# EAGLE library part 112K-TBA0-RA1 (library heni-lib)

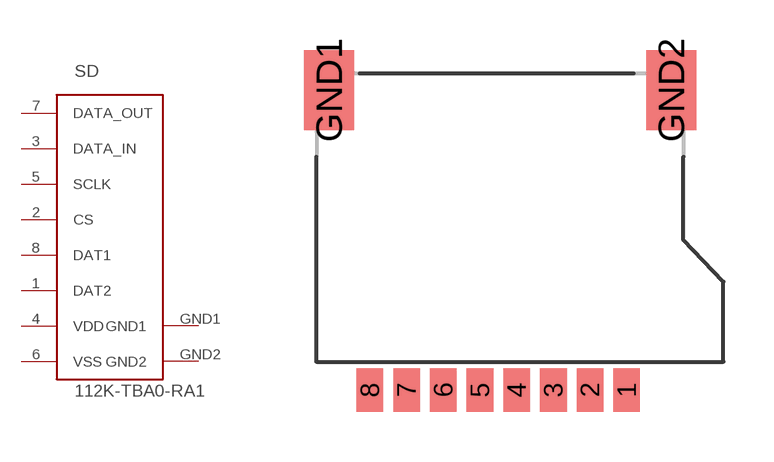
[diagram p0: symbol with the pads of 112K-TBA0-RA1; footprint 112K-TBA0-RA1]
Designator prefix SD

## 112K-TBA0-RA1  [112K-TBA0-RA1]
1  DAT2
2  CS
3  DATA_IN
4  VDD
5  SCLK
6  VSS
7  DATA_OUT
8  DAT1
GND1  GND1
GND2  GND2

## Footprint 112K-TBA0-RA1 (pad centres in mm)
smd 0.8 x 1.3: 1 3.2,0; 2 2.1,0; 3 1,0; 4 -0.1,0; 5 -1.2,0; 6 -2.3,0; 7 -3.4,0; 8 -4.5,0
smd 1.5 x 2.4: GND1 -5.73,9; GND2 4.53,9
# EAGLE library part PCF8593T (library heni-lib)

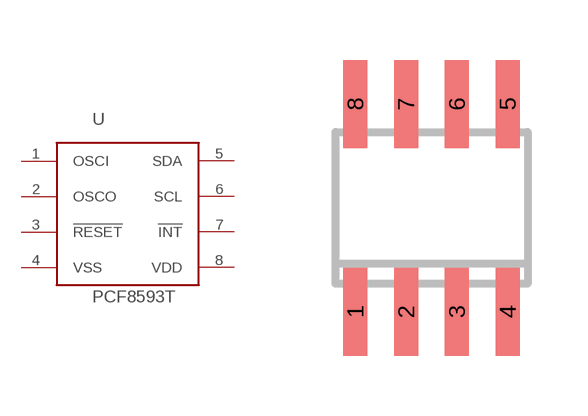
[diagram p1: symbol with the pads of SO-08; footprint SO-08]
Designator prefix U

## PCF8593T  [SO-08]
1  OSCI
2  OSCO
3  !RESET
4  VSS
5  SDA
6  SCL
7  !INT
8  VDD

## Footprint SO-08 (pad centres in mm)
Small Outline Narrow Plastic Gull Wing 150-mil body, package type SN
smd 0.6 x 2.2: 1 -1.905,-2.6; 2 -0.635,-2.6; 3 0.635,-2.6; 4 1.905,-2.6; 5 1.905,2.6; 6 0.635,2.6; 7 -0.635,2.6; 8 -1.905,2.6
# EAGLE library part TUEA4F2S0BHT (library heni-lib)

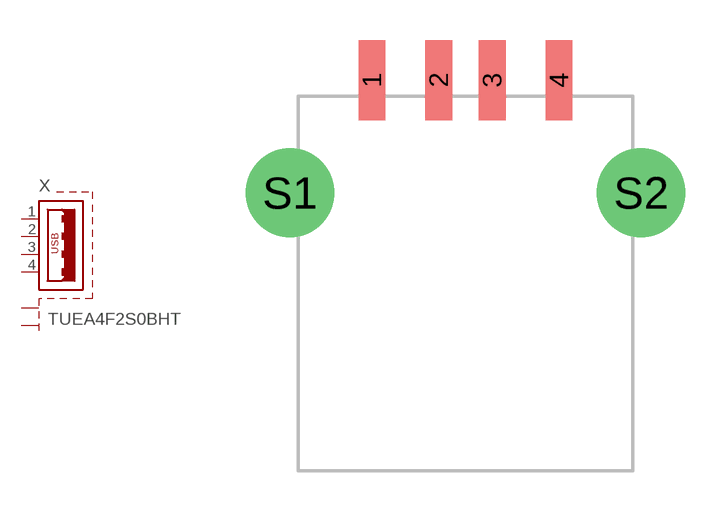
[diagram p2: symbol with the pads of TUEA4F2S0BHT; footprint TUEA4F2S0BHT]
Designator prefix X

## TUEA4F2S0BHT  [TUEA4F2S0BHT]
1  VCC  pas
2  D-  pas
3  D+  pas
4  GND  pas
S1  S1  pas
S2  S2  pas

## Footprint TUEA4F2S0BHT (pad centres in mm)
smd 1 x 3: 1 -3.5,14.61; 2 -1,14.61; 3 1,14.61; 4 3.5,14.61
drill 2.3: S1 -6.57,10.4; S2 6.57,10.4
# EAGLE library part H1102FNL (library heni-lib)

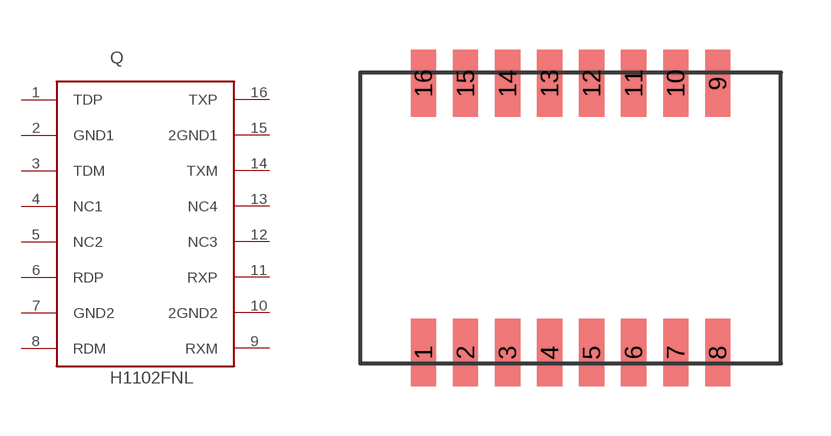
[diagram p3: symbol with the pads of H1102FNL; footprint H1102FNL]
Designator prefix Q

## H1102FNL  [H1102FNL]
1  TDP
2  GND1
3  TDM
4  NC1
5  NC2
6  RDP
7  GND2
8  RDM
9  RXM
10  2GND2
11  RXP
12  NC3
13  NC4
14  TXM
15  2GND1
16  TXP

## Footprint H1102FNL (pad centres in mm)
smd 0.762 x 2.032: 1 -4.445,-4.064; 2 -3.175,-4.064; 3 -1.905,-4.064; 4 -0.635,-4.064; 5 0.635,-4.064; 6 1.905,-4.064; 7 3.175,-4.064; 8 4.445,-4.064; 9 4.445,4.064; 10 3.175,4.064; 11 1.905,4.064; 12 0.635,4.064; 13 -0.635,4.064; 14 -1.905,4.064; 15 -3.175,4.064; 16 -4.445,4.064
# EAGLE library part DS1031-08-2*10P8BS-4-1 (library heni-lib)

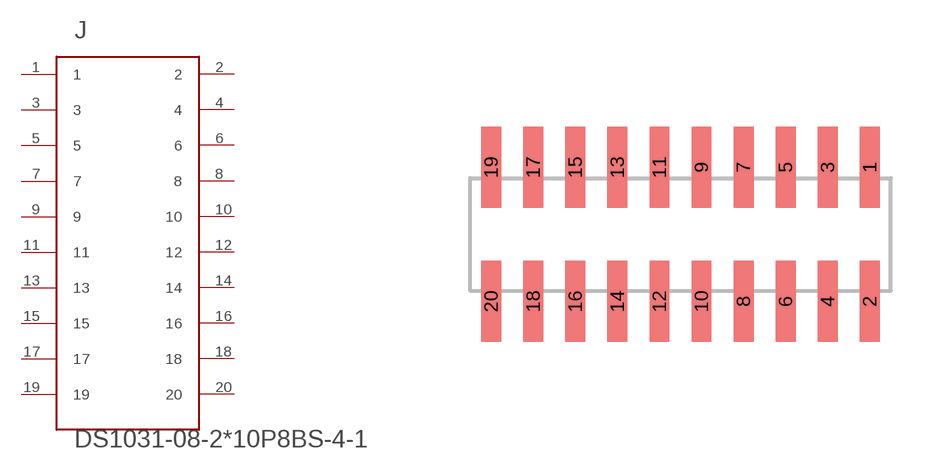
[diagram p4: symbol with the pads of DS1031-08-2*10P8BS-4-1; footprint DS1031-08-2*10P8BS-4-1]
Designator prefix J

## DS1031-08-210P8BS-4-1  [DS1031-08-2*10P8BS-4-1]
1  1
2  2
3  3
4  4
5  5
6  6
7  7
8  8
9  9
10  10
11  11
12  12
13  13
14  14
15  15
16  16
17  17
18  18
19  19
20  20

## Footprint DS1031-08-2*10P8BS-4-1 (pad centres in mm)
smd 0.6 x 2.45: 1 5.715,2.025; 2 5.715,-2.025; 3 4.445,2.025; 4 4.445,-2.025; 5 3.175,2.025; 6 3.175,-2.025; 7 1.905,2.025; 8 1.905,-2.025; 9 0.635,2.025; 10 0.635,-2.025; 11 -0.635,2.025; 12 -0.635,-2.025; 13 -1.905,2.025; 14 -1.905,-2.025; 15 -3.175,2.025; 16 -3.175,-2.025; 17 -4.445,2.025; 18 -4.445,-2.025; 19 -5.715,2.025; 20 -5.715,-2.025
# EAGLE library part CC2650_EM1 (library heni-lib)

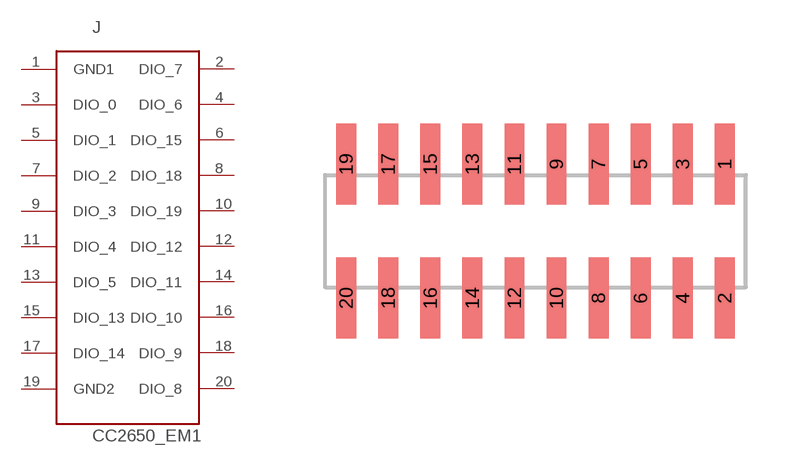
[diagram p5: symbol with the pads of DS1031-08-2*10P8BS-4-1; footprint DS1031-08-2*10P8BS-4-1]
Designator prefix J

## CC2650_EM1  [DS1031-08-2*10P8BS-4-1]
1  GND1
2  DIO_7
3  DIO_0
4  DIO_6
5  DIO_1
6  DIO_15
7  DIO_2
8  DIO_18
9  DIO_3
10  DIO_19
11  DIO_4
12  DIO_12
13  DIO_5
14  DIO_11
15  DIO_13
16  DIO_10
17  DIO_14
18  DIO_9
19  GND2
20  DIO_8

## Footprint DS1031-08-2*10P8BS-4-1 (pad centres in mm)
smd 0.6 x 2.45: 1 5.715,2.025; 2 5.715,-2.025; 3 4.445,2.025; 4 4.445,-2.025; 5 3.175,2.025; 6 3.175,-2.025; 7 1.905,2.025; 8 1.905,-2.025; 9 0.635,2.025; 10 0.635,-2.025; 11 -0.635,2.025; 12 -0.635,-2.025; 13 -1.905,2.025; 14 -1.905,-2.025; 15 -3.175,2.025; 16 -3.175,-2.025; 17 -4.445,2.025; 18 -4.445,-2.025; 19 -5.715,2.025; 20 -5.715,-2.025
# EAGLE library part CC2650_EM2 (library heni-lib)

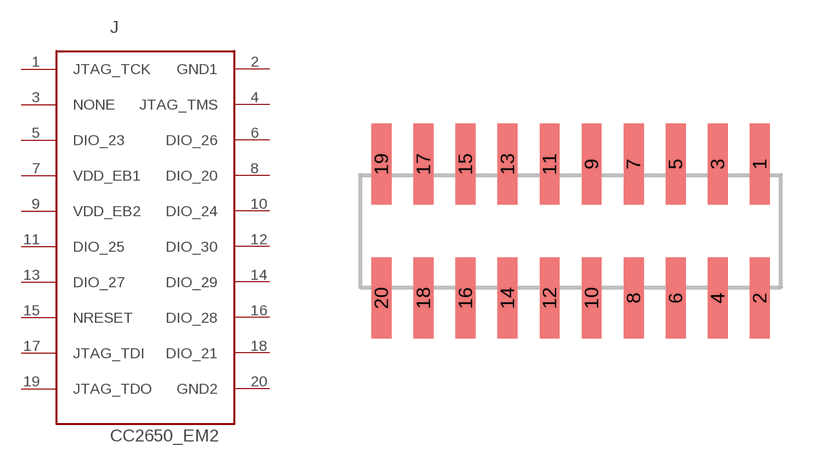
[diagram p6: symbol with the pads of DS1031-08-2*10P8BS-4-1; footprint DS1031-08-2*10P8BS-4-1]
Designator prefix J

## CC2650_EM2  [DS1031-08-2*10P8BS-4-1]
1  JTAG_TCK
2  GND1
3  NONE
4  JTAG_TMS
5  DIO_23
6  DIO_26
7  VDD_EB1
8  DIO_20
9  VDD_EB2
10  DIO_24
11  DIO_25
12  DIO_30
13  DIO_27
14  DIO_29
15  NRESET
16  DIO_28
17  JTAG_TDI
18  DIO_21
19  JTAG_TDO
20  GND2

## Footprint DS1031-08-2*10P8BS-4-1 (pad centres in mm)
smd 0.6 x 2.45: 1 5.715,2.025; 2 5.715,-2.025; 3 4.445,2.025; 4 4.445,-2.025; 5 3.175,2.025; 6 3.175,-2.025; 7 1.905,2.025; 8 1.905,-2.025; 9 0.635,2.025; 10 0.635,-2.025; 11 -0.635,2.025; 12 -0.635,-2.025; 13 -1.905,2.025; 14 -1.905,-2.025; 15 -3.175,2.025; 16 -3.175,-2.025; 17 -4.445,2.025; 18 -4.445,-2.025; 19 -5.715,2.025; 20 -5.715,-2.025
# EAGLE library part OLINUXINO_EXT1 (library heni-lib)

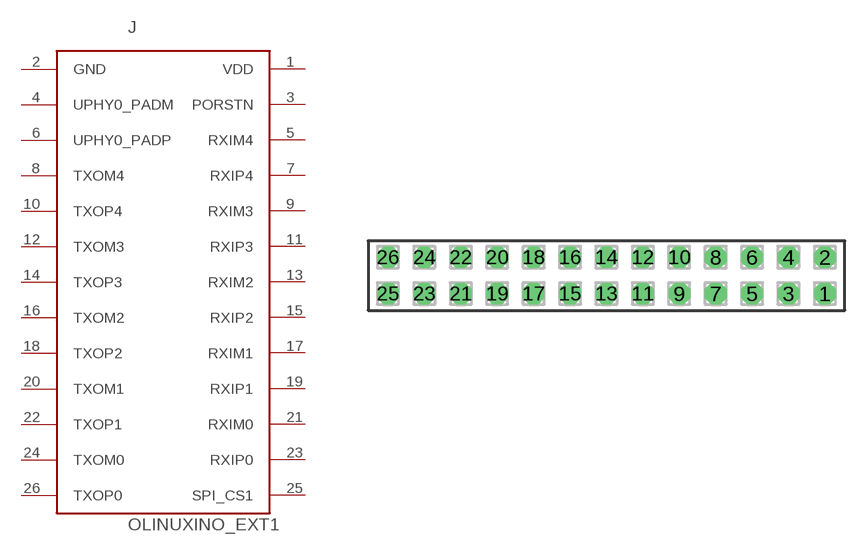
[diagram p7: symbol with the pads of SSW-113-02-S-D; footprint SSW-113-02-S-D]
Designator prefix J

## OLINUXINO_EXT1  [SSW-113-02-S-D]
1  VDD
2  GND
3  PORSTN
4  UPHY0_PADM
5  RXIM4
6  UPHY0_PADP
7  RXIP4
8  TXOM4
9  RXIM3
10  TXOP4
11  RXIP3
12  TXOM3
13  RXIM2
14  TXOP3
15  RXIP2
16  TXOM2
17  RXIM1
18  TXOP2
19  RXIP1
20  TXOM1
21  RXIM0
22  TXOP1
23  RXIP0
24  TXOM0
25  SPI_CS1
26  TXOP0

## Footprint SSW-113-02-S-D (pad centres in mm)
THROUGH-HOLE .025" SQ POST SOCKET Source: Samtec SSW.pdf
drill 1 pad 1.5 octagon: 1 15.24,-1.27; 2 15.24,1.27; 3 12.7,-1.27; 4 12.7,1.27; 5 10.16,-1.27; 6 10.16,1.27; 7 7.62,-1.27; 8 7.62,1.27; 9 5.08,-1.27; 10 5.08,1.27; 11 2.54,-1.27; 12 2.54,1.27; 13 0,-1.27; 14 0,1.27; 15 -2.54,-1.27; 16 -2.54,1.27; 17 -5.08,-1.27; 18 -5.08,1.27; 19 -7.62,-1.27; 20 -7.62,1.27; 21 -10.16,-1.27; 22 -10.16,1.27; 23 -12.7,-1.27; 24 -12.7,1.27; 25 -15.24,-1.27; 26 -15.24,1.27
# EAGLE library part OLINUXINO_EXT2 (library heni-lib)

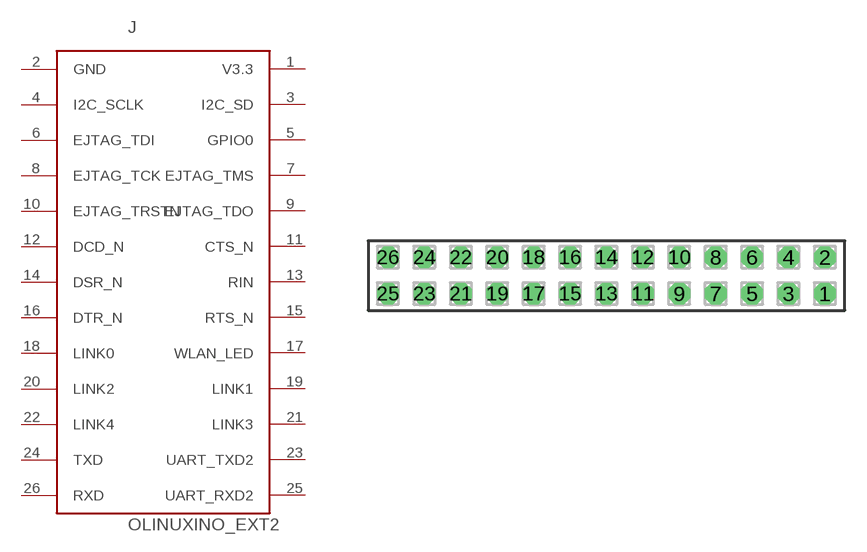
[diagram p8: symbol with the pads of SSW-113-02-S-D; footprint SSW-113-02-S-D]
Designator prefix J

## OLINUXINO_EXT2  [SSW-113-02-S-D]
1  V3.3
2  GND
3  I2C_SD
4  I2C_SCLK
5  GPIO0
6  EJTAG_TDI
7  EJTAG_TMS
8  EJTAG_TCK
9  EJTAG_TDO
10  EJTAG_TRSTN
11  CTS_N
12  DCD_N
13  RIN
14  DSR_N
15  RTS_N
16  DTR_N
17  WLAN_LED
18  LINK0
19  LINK1
20  LINK2
21  LINK3
22  LINK4
23  UART_TXD2
24  TXD
25  UART_RXD2
26  RXD

## Footprint SSW-113-02-S-D (pad centres in mm)
THROUGH-HOLE .025" SQ POST SOCKET Source: Samtec SSW.pdf
drill 1 pad 1.5 octagon: 1 15.24,-1.27; 2 15.24,1.27; 3 12.7,-1.27; 4 12.7,1.27; 5 10.16,-1.27; 6 10.16,1.27; 7 7.62,-1.27; 8 7.62,1.27; 9 5.08,-1.27; 10 5.08,1.27; 11 2.54,-1.27; 12 2.54,1.27; 13 0,-1.27; 14 0,1.27; 15 -2.54,-1.27; 16 -2.54,1.27; 17 -5.08,-1.27; 18 -5.08,1.27; 19 -7.62,-1.27; 20 -7.62,1.27; 21 -10.16,-1.27; 22 -10.16,1.27; 23 -12.7,-1.27; 24 -12.7,1.27; 25 -15.24,-1.27; 26 -15.24,1.27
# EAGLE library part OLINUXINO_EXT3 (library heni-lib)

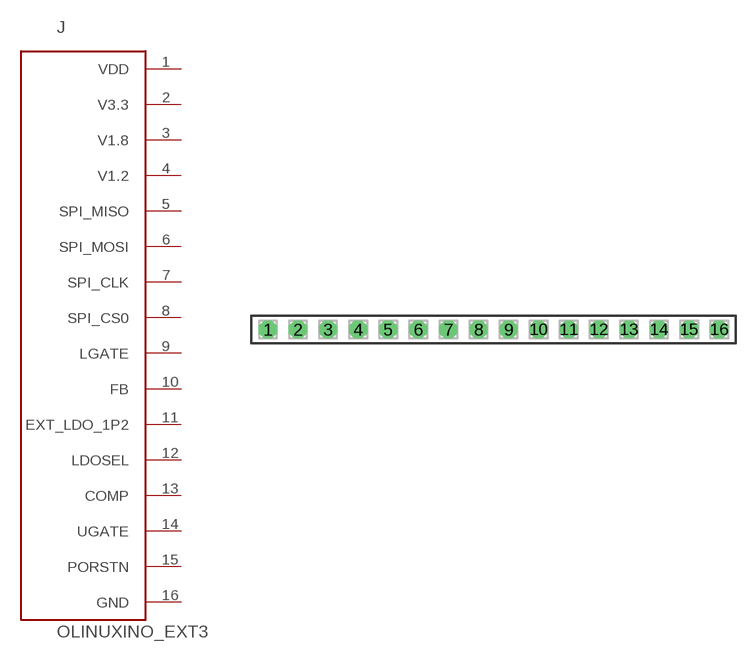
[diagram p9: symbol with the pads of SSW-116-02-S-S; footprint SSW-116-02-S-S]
Designator prefix J

## OLINUXINO_EXT3  [SSW-116-02-S-S]
1  VDD
2  V3.3
3  V1.8
4  V1.2
5  SPI_MISO
6  SPI_MOSI
7  SPI_CLK
8  SPI_CS0
9  LGATE
10  FB
11  EXT_LDO_1P2
12  LDOSEL
13  COMP
14  UGATE
15  PORSTN
16  GND

## Footprint SSW-116-02-S-S (pad centres in mm)
THROUGH-HOLE .025" SQ POST SOCKET Source: Samtec SSW.pdf
drill 1 pad 1.5 octagon: 1 -19.05,0; 2 -16.51,0; 3 -13.97,0; 4 -11.43,0; 5 -8.89,0; 6 -6.35,0; 7 -3.81,0; 8 -1.27,0; 9 1.27,0; 10 3.81,0; 11 6.35,0; 12 8.89,0; 13 11.43,0; 14 13.97,0; 15 16.51,0; 16 19.05,0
